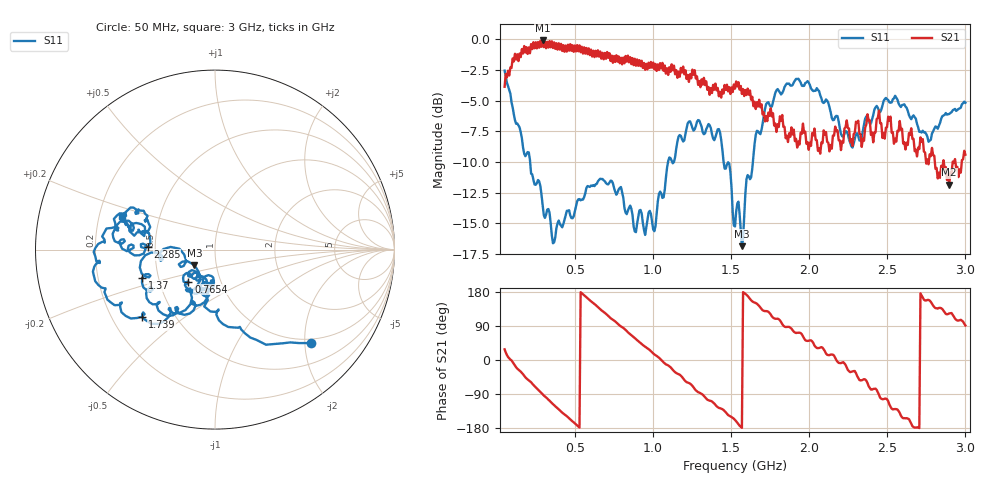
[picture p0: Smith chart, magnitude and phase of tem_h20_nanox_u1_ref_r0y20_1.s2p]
! nanovna_capture.py 2026-10-26T21:08:39+0900
! NanoVNA-F_V2 fw 0.6.0 SN 4A3639384505514B
! cal: load open short thru cal'ed  over 50000000-3000000000 Hz, 201 points
! points 401, avg 4
! TEM h=20, genuine Nano X, flat back down, 0 deg, moved 20 mm along the cell toward PORT 2
# HZ S RI R 50
! S12 and S22 are not measured (written as 0)
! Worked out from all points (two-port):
!   401 points, 50 MHz to 3 GHz, reference 50 ohm
!   highest |S21| = -0.08 dB at 293.4 MHz (marker M1); lowest = -11.9 dB at 2.897 GHz (marker M2)
!   |S21| within 3 dB of the highest: 64.94 MHz to 1.156 GHz (1.091 GHz wide, 179 % of centre); 1.157 GHz to 1.214 GHz (56.76 MHz wide, 4.79 % of centre) (the widest 2 of 7)
!   lowest |S11| = -16.9 dB at 1.569 GHz (marker M3), VSWR 1.33, Z = 39.2 - j6.9 ohm
!   |S11| at or under -10 dB: 213.3 MHz to 1.096 GHz (883.1 MHz wide, 135 % of centre); 1.123 GHz to 1.134 GHz (11.41 MHz wide, 1.01 % of centre); 1.452 GHz to 1.64 GHz (187.4 MHz wide, 12.1 % of centre)
!   S12 and S22 are empty: the file has one direction only
!   S11 on the Smith chart (normalised r, x): 50 MHz: 0.91, -2.14; 765.4 MHz: 0.70, -0.26; 1.37 GHz: 0.40, -0.16; 1.739 GHz: 0.33, -0.36; 2.285 GHz: 0.45, +0.02; 3 GHz: 0.30, +0.16
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5e7  0.5349 -0.5202  0.5656 0.3018  0 0  0 0
1.01625e8  0.1967 -0.4899  0.8326 -0.082  0 0  0 0
1.60625e8  0.0218 -0.3942  0.7562 -0.5123  0 0  0 0
2.93375e8  -0.0782 -0.1973  -0.00393 -0.9906  0 0  0 0
4.11375e8  -0.0214 -0.1723  -0.6897 -0.6667  0 0  0 0
5.44125e8  -0.0365 -0.2192  -0.9317 0.0606  0 0  0 0
6.62125e8  -0.1127 -0.2454  -0.6202 0.6425  0 0  0 0
7.65375e8  -0.1484 -0.1788  -0.135 0.8512  0 0  0 0
9.12875e8  -0.1167 -0.1629  0.5599 0.6031  0 0  0 0
1.03825e9  -0.064 -0.2251  0.7466 0.0783  0 0  0 0
1.207875e9  -0.2138 -0.3525  0.4196 -0.6197  0 0  0 0
1.370125e9  -0.406 -0.1573  -0.1956 -0.6024  0 0  0 0
1.525e9  -0.1598 -0.0651  -0.5854 -0.2325  0 0  0 0
1.56925e9  -0.1144 -0.0862  -0.599 -0.0108  0 0  0 0
1.738875e9  -0.4064 -0.3771  -0.3041 0.4007  0 0  0 0
2.019125e9  -0.6198 0.0446  0.2709 0.3144  0 0  0 0
2.284625e9  -0.3753 0.0159  0.3586 -0.2005  0 0  0 0
2.387875e9  -0.4543 0.0225  0.1304 -0.4496  0 0  0 0
2.51325e9  -0.5398 0.1223  -0.2137 -0.4146  0 0  0 0
2.653375e9  -0.4271 0.2021  -0.4244 -0.0908  0 0  0 0
2.89675e9  -0.4785 0.1316  -0.139 0.2142  0 0  0 0
3e9  -0.518 0.1896  -0.00666 0.3385  0 0  0 0
